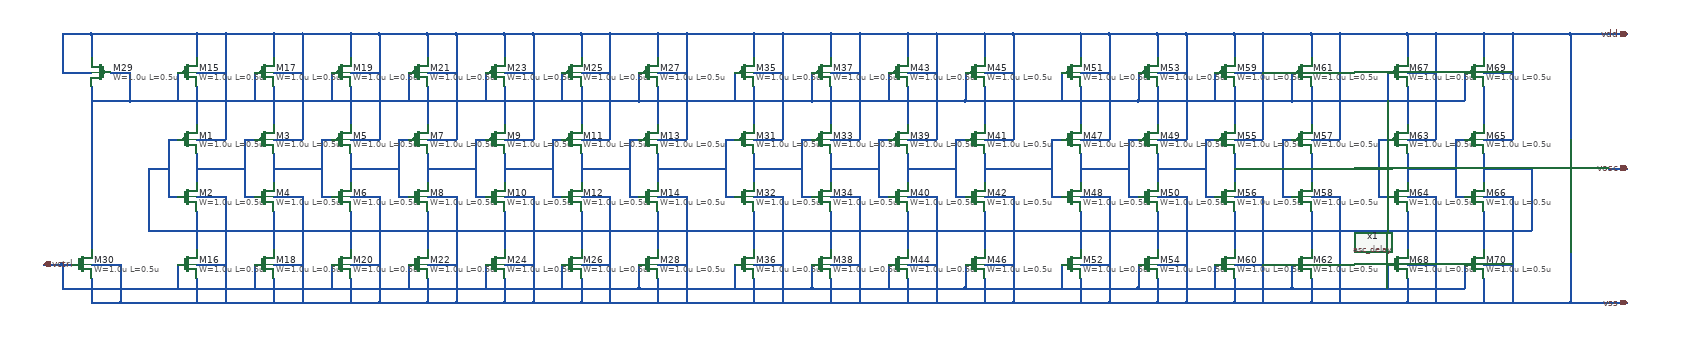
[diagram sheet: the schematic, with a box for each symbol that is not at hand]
v {xschem version=3.4.7 file_version=1.2}
G {}
K {}
V {}
S {}
E {}
N 1840 -1350 1840 -1290 {lab=#net1}
N 2000 -1350 2000 -1290 {lab=#net2}
N 2160 -1350 2160 -1290 {lab=#net3}
N 2320 -1350 2320 -1290 {lab=#net4}
N 2480 -1350 2480 -1290 {lab=#net5}
N 2640 -1350 2640 -1290 {lab=#net6}
N 2800 -1350 2800 -1290 {lab=#net7}
N 1840 -1230 1840 -1170 {lab=#net8}
N 1840 -1110 1840 -1030 {lab=#net9}
N 2000 -1110 2000 -1030 {lab=#net10}
N 2160 -1110 2160 -1030 {lab=#net11}
N 2320 -1110 2320 -1030 {lab=#net12}
N 2480 -1110 2480 -1030 {lab=#net13}
N 2640 -1110 2640 -1030 {lab=#net14}
N 2800 -1110 2800 -1030 {lab=#net15}
N 2000 -1230 2000 -1170 {lab=#net16}
N 2160 -1230 2160 -1170 {lab=#net17}
N 2320 -1230 2320 -1170 {lab=#net18}
N 2480 -1230 2480 -1170 {lab=#net19}
N 2640 -1230 2640 -1170 {lab=#net20}
N 2800 -1230 2800 -1170 {lab=#net21}
N 1780 -1260 1800 -1260 {lab=#net22}
N 1780 -1260 1780 -1140 {lab=#net22}
N 1780 -1140 1800 -1140 {lab=#net22}
N 1940 -1260 1960 -1260 {lab=#net8}
N 1940 -1260 1940 -1140 {lab=#net8}
N 1940 -1140 1960 -1140 {lab=#net8}
N 2100 -1260 2120 -1260 {lab=#net16}
N 2100 -1260 2100 -1140 {lab=#net16}
N 2100 -1140 2120 -1140 {lab=#net16}
N 2260 -1260 2280 -1260 {lab=#net17}
N 2260 -1260 2260 -1140 {lab=#net17}
N 2260 -1140 2280 -1140 {lab=#net17}
N 2420 -1260 2440 -1260 {lab=#net18}
N 2420 -1260 2420 -1140 {lab=#net18}
N 2420 -1140 2440 -1140 {lab=#net18}
N 2580 -1260 2600 -1260 {lab=#net19}
N 2580 -1260 2580 -1140 {lab=#net19}
N 2580 -1140 2600 -1140 {lab=#net19}
N 2740 -1260 2760 -1260 {lab=#net20}
N 2740 -1260 2740 -1140 {lab=#net20}
N 2740 -1140 2760 -1140 {lab=#net20}
N 1840 -1200 1940 -1200 {lab=#net8}
N 2000 -1200 2100 -1200 {lab=#net16}
N 2160 -1200 2260 -1200 {lab=#net17}
N 2320 -1200 2420 -1200 {lab=#net18}
N 2480 -1200 2580 -1200 {lab=#net19}
N 2640 -1200 2740 -1200 {lab=#net20}
N 1740 -1200 1780 -1200 {lab=#net22}
N 1740 -1200 1740 -1070 {lab=#net22}
N 1740 -1070 2900 -1070 {lab=#net22}
N 2800 -1200 2900 -1200 {lab=#net21}
N 1840 -1140 1900 -1140 {lab=#net23}
N 1900 -1140 1900 -920 {lab=#net23}
N 1840 -1000 1900 -1000 {lab=#net23}
N 1840 -970 1840 -920 {lab=#net23}
N 1840 -920 1900 -920 {lab=#net23}
N 2000 -1140 2060 -1140 {lab=#net23}
N 2060 -1140 2060 -920 {lab=#net23}
N 2000 -1000 2060 -1000 {lab=#net23}
N 2000 -970 2000 -920 {lab=#net23}
N 2000 -920 2060 -920 {lab=#net23}
N 2160 -1140 2220 -1140 {lab=#net23}
N 2220 -1140 2220 -920 {lab=#net23}
N 2160 -1000 2220 -1000 {lab=#net23}
N 2160 -970 2160 -920 {lab=#net23}
N 2160 -920 2220 -920 {lab=#net23}
N 2320 -1140 2380 -1140 {lab=#net23}
N 2380 -1140 2380 -920 {lab=#net23}
N 2320 -1000 2380 -1000 {lab=#net23}
N 2320 -970 2320 -920 {lab=#net23}
N 2320 -920 2380 -920 {lab=#net23}
N 2480 -1140 2540 -1140 {lab=#net23}
N 2540 -1140 2540 -920 {lab=#net23}
N 2480 -1000 2540 -1000 {lab=#net23}
N 2480 -970 2480 -920 {lab=#net23}
N 2480 -920 2540 -920 {lab=#net23}
N 2640 -1140 2700 -1140 {lab=#net23}
N 2700 -1140 2700 -920 {lab=#net23}
N 2640 -1000 2700 -1000 {lab=#net23}
N 2640 -970 2640 -920 {lab=#net23}
N 2640 -920 2700 -920 {lab=#net23}
N 2800 -1140 2860 -1140 {lab=#net23}
N 2860 -1140 2860 -920 {lab=#net23}
N 2800 -1000 2860 -1000 {lab=#net23}
N 2800 -970 2800 -920 {lab=#net23}
N 2800 -920 2860 -920 {lab=#net23}
N 1840 -1370 1840 -1350 {lab=#net1}
N 2000 -1370 2000 -1350 {lab=#net2}
N 2160 -1370 2160 -1350 {lab=#net3}
N 2320 -1370 2320 -1350 {lab=#net4}
N 2480 -1370 2480 -1350 {lab=#net5}
N 2640 -1370 2640 -1350 {lab=#net6}
N 2800 -1370 2800 -1350 {lab=#net7}
N 1840 -1260 1900 -1260 {lab=#net24}
N 1900 -1480 1900 -1260 {lab=#net24}
N 1840 -1400 1900 -1400 {lab=#net24}
N 1840 -1480 1840 -1430 {lab=#net24}
N 1840 -1480 1900 -1480 {lab=#net24}
N 2000 -1260 2060 -1260 {lab=#net24}
N 2060 -1480 2060 -1260 {lab=#net24}
N 2000 -1400 2060 -1400 {lab=#net24}
N 2000 -1480 2000 -1430 {lab=#net24}
N 2000 -1480 2060 -1480 {lab=#net24}
N 2160 -1260 2220 -1260 {lab=#net24}
N 2220 -1480 2220 -1260 {lab=#net24}
N 2160 -1400 2220 -1400 {lab=#net24}
N 2160 -1480 2160 -1430 {lab=#net24}
N 2160 -1480 2220 -1480 {lab=#net24}
N 2320 -1260 2380 -1260 {lab=#net24}
N 2380 -1480 2380 -1260 {lab=#net24}
N 2320 -1400 2380 -1400 {lab=#net24}
N 2320 -1480 2320 -1430 {lab=#net24}
N 2320 -1480 2380 -1480 {lab=#net24}
N 2480 -1260 2540 -1260 {lab=#net24}
N 2540 -1480 2540 -1260 {lab=#net24}
N 2480 -1400 2540 -1400 {lab=#net24}
N 2480 -1480 2480 -1430 {lab=#net24}
N 2480 -1480 2540 -1480 {lab=#net24}
N 2640 -1260 2700 -1260 {lab=#net24}
N 2700 -1480 2700 -1260 {lab=#net24}
N 2640 -1400 2700 -1400 {lab=#net24}
N 2640 -1480 2640 -1430 {lab=#net24}
N 2640 -1480 2700 -1480 {lab=#net24}
N 2800 -1260 2860 -1260 {lab=#net24}
N 2860 -1480 2860 -1260 {lab=#net24}
N 2800 -1400 2860 -1400 {lab=#net24}
N 2800 -1480 2800 -1430 {lab=#net24}
N 2800 -1480 2860 -1480 {lab=#net24}
N 1900 -1480 2000 -1480 {lab=#net24}
N 2060 -1480 2160 -1480 {lab=#net24}
N 2220 -1480 2320 -1480 {lab=#net24}
N 2380 -1480 2480 -1480 {lab=#net24}
N 2540 -1480 2640 -1480 {lab=#net24}
N 2700 -1480 2800 -1480 {lab=#net24}
N 1900 -920 2000 -920 {lab=#net23}
N 2060 -920 2160 -920 {lab=#net23}
N 2220 -920 2320 -920 {lab=#net23}
N 2380 -920 2480 -920 {lab=#net23}
N 2540 -920 2640 -920 {lab=#net23}
N 2700 -920 2800 -920 {lab=#net23}
N 1560 -1400 1620 -1400 {lab=#net24}
N 1620 -1480 1620 -1430 {lab=#net24}
N 1620 -1480 1680 -1480 {lab=#net24}
N 1560 -1480 1560 -1400 {lab=#net24}
N 1560 -1480 1620 -1480 {lab=#net24}
N 1620 -1000 1680 -1000 {lab=#net23}
N 1620 -970 1620 -920 {lab=#net23}
N 1620 -920 1680 -920 {lab=#net23}
N 1680 -1000 1680 -920 {lab=#net23}
N 1620 -1370 1620 -1030 {lab=#net25}
N 1620 -1340 1700 -1340 {lab=#net25}
N 1660 -1400 1700 -1400 {lab=#net25}
N 1700 -1400 1700 -1340 {lab=#net25}
N 1680 -920 1840 -920 {lab=#net23}
N 1680 -1480 1840 -1480 {lab=#net24}
N 2860 -1480 2900 -1480 {lab=#net24}
N 2860 -920 2900 -920 {lab=#net23}
N 2900 -1200 2920 -1200 {lab=#net21}
N 2920 -1200 2940 -1200 {lab=#net21}
N 1700 -1340 2760 -1340 {lab=#net25}
N 2760 -1400 2760 -1340 {lab=#net25}
N 2600 -1400 2600 -1340 {lab=#net25}
N 2440 -1400 2440 -1340 {lab=#net25}
N 2280 -1400 2280 -1340 {lab=#net25}
N 2120 -1400 2120 -1340 {lab=#net25}
N 1960 -1400 1960 -1340 {lab=#net25}
N 1800 -1400 1800 -1340 {lab=#net25}
N 1560 -1000 1560 -950 {lab=vctrl}
N 1560 -950 2760 -950 {lab=vctrl}
N 2760 -1000 2760 -950 {lab=vctrl}
N 2600 -1000 2600 -960 {lab=vctrl}
N 2600 -960 2600 -950 {lab=vctrl}
N 2440 -1000 2440 -950 {lab=vctrl}
N 2280 -1000 2280 -950 {lab=vctrl}
N 2120 -1000 2120 -950 {lab=vctrl}
N 1960 -1000 1960 -950 {lab=vctrl}
N 1800 -1000 1800 -950 {lab=vctrl}
N 1560 -1000 1580 -1000 {lab=vctrl}
N 4780 -1200 4820 -1200 {lab=vosc}
N 4700 -1140 4700 -920 {lab=vss}
N 4700 -1480 4700 -1260 {lab=vdd}
N 4700 -1480 4820 -1480 {lab=vdd}
N 4700 -920 4820 -920 {lab=vss}
N 1520 -1000 1560 -1000 {lab=vctrl}
N 3000 -1350 3000 -1290 {lab=#net26}
N 3160 -1350 3160 -1290 {lab=#net27}
N 3000 -1110 3000 -1030 {lab=#net28}
N 3160 -1110 3160 -1030 {lab=#net29}
N 3000 -1230 3000 -1170 {lab=#net30}
N 3160 -1230 3160 -1170 {lab=#net31}
N 2940 -1260 2960 -1260 {lab=#net21}
N 2940 -1260 2940 -1140 {lab=#net21}
N 2940 -1140 2960 -1140 {lab=#net21}
N 3100 -1260 3120 -1260 {lab=#net30}
N 3100 -1260 3100 -1140 {lab=#net30}
N 3100 -1140 3120 -1140 {lab=#net30}
N 3000 -1200 3100 -1200 {lab=#net30}
N 3160 -1200 3260 -1200 {lab=#net31}
N 3000 -1140 3060 -1140 {lab=#net23}
N 3060 -1140 3060 -920 {lab=#net23}
N 3000 -1000 3060 -1000 {lab=#net23}
N 3000 -970 3000 -920 {lab=#net23}
N 3000 -920 3060 -920 {lab=#net23}
N 3160 -1140 3220 -1140 {lab=#net23}
N 3220 -1140 3220 -920 {lab=#net23}
N 3160 -1000 3220 -1000 {lab=#net23}
N 3160 -970 3160 -920 {lab=#net23}
N 3160 -920 3220 -920 {lab=#net23}
N 3000 -1370 3000 -1350 {lab=#net26}
N 3160 -1370 3160 -1350 {lab=#net27}
N 3000 -1260 3060 -1260 {lab=#net24}
N 3060 -1480 3060 -1260 {lab=#net24}
N 3000 -1400 3060 -1400 {lab=#net24}
N 3000 -1480 3000 -1430 {lab=#net24}
N 3000 -1480 3060 -1480 {lab=#net24}
N 3160 -1260 3220 -1260 {lab=#net24}
N 3220 -1480 3220 -1260 {lab=#net24}
N 3160 -1400 3220 -1400 {lab=#net24}
N 3160 -1480 3160 -1430 {lab=#net24}
N 3160 -1480 3220 -1480 {lab=#net24}
N 3060 -1480 3160 -1480 {lab=#net24}
N 3060 -920 3160 -920 {lab=#net23}
N 3220 -1480 3260 -1480 {lab=#net24}
N 3220 -920 3260 -920 {lab=#net23}
N 3120 -1400 3120 -1340 {lab=#net25}
N 2960 -1400 2960 -1340 {lab=#net25}
N 3120 -1000 3120 -950 {lab=vctrl}
N 2960 -1000 2960 -960 {lab=vctrl}
N 2960 -960 2960 -950 {lab=vctrl}
N 2900 -1070 3260 -1070 {lab=#net22}
N 2900 -1480 3000 -1480 {lab=#net24}
N 2900 -920 3000 -920 {lab=#net23}
N 2760 -950 3120 -950 {lab=vctrl}
N 2760 -1340 3120 -1340 {lab=#net25}
N 3320 -1350 3320 -1290 {lab=#net32}
N 3480 -1350 3480 -1290 {lab=#net33}
N 3320 -1110 3320 -1030 {lab=#net34}
N 3480 -1110 3480 -1030 {lab=#net35}
N 3320 -1230 3320 -1170 {lab=#net36}
N 3480 -1230 3480 -1170 {lab=#net37}
N 3260 -1260 3280 -1260 {lab=#net31}
N 3260 -1260 3260 -1140 {lab=#net31}
N 3260 -1140 3280 -1140 {lab=#net31}
N 3420 -1260 3440 -1260 {lab=#net36}
N 3420 -1260 3420 -1140 {lab=#net36}
N 3420 -1140 3440 -1140 {lab=#net36}
N 3320 -1200 3420 -1200 {lab=#net36}
N 3480 -1200 3580 -1200 {lab=#net37}
N 3320 -1140 3380 -1140 {lab=#net23}
N 3380 -1140 3380 -920 {lab=#net23}
N 3320 -1000 3380 -1000 {lab=#net23}
N 3320 -970 3320 -920 {lab=#net23}
N 3320 -920 3380 -920 {lab=#net23}
N 3480 -1140 3540 -1140 {lab=#net23}
N 3540 -1140 3540 -920 {lab=#net23}
N 3480 -1000 3540 -1000 {lab=#net23}
N 3480 -970 3480 -920 {lab=#net23}
N 3480 -920 3540 -920 {lab=#net23}
N 3320 -1370 3320 -1350 {lab=#net32}
N 3480 -1370 3480 -1350 {lab=#net33}
N 3320 -1260 3380 -1260 {lab=#net24}
N 3380 -1480 3380 -1260 {lab=#net24}
N 3320 -1400 3380 -1400 {lab=#net24}
N 3320 -1480 3320 -1430 {lab=#net24}
N 3320 -1480 3380 -1480 {lab=#net24}
N 3480 -1260 3540 -1260 {lab=#net24}
N 3540 -1480 3540 -1260 {lab=#net24}
N 3480 -1400 3540 -1400 {lab=#net24}
N 3480 -1480 3480 -1430 {lab=#net24}
N 3480 -1480 3540 -1480 {lab=#net24}
N 3380 -1480 3480 -1480 {lab=#net24}
N 3380 -920 3480 -920 {lab=#net23}
N 3540 -1480 3580 -1480 {lab=#net24}
N 3540 -920 3580 -920 {lab=#net23}
N 3580 -1200 3600 -1200 {lab=#net37}
N 3600 -1200 3620 -1200 {lab=#net37}
N 3440 -1400 3440 -1340 {lab=#net25}
N 3280 -1400 3280 -1340 {lab=#net25}
N 3440 -1000 3440 -950 {lab=vctrl}
N 3280 -1000 3280 -960 {lab=vctrl}
N 3280 -960 3280 -950 {lab=vctrl}
N 3680 -1350 3680 -1290 {lab=#net38}
N 3840 -1350 3840 -1290 {lab=#net39}
N 3680 -1110 3680 -1030 {lab=#net40}
N 3840 -1110 3840 -1030 {lab=#net41}
N 3680 -1230 3680 -1170 {lab=#net42}
N 3840 -1230 3840 -1170 {lab=#net43}
N 3620 -1260 3640 -1260 {lab=#net37}
N 3620 -1260 3620 -1140 {lab=#net37}
N 3620 -1140 3640 -1140 {lab=#net37}
N 3780 -1260 3800 -1260 {lab=#net42}
N 3780 -1260 3780 -1140 {lab=#net42}
N 3780 -1140 3800 -1140 {lab=#net42}
N 3680 -1200 3780 -1200 {lab=#net42}
N 3840 -1200 3940 -1200 {lab=#net43}
N 3680 -1140 3740 -1140 {lab=#net23}
N 3740 -1140 3740 -920 {lab=#net23}
N 3680 -1000 3740 -1000 {lab=#net23}
N 3680 -970 3680 -920 {lab=#net23}
N 3680 -920 3740 -920 {lab=#net23}
N 3840 -1140 3900 -1140 {lab=#net23}
N 3900 -1140 3900 -920 {lab=#net23}
N 3840 -1000 3900 -1000 {lab=#net23}
N 3840 -970 3840 -920 {lab=#net23}
N 3840 -920 3900 -920 {lab=#net23}
N 3680 -1370 3680 -1350 {lab=#net38}
N 3840 -1370 3840 -1350 {lab=#net39}
N 3680 -1260 3740 -1260 {lab=#net24}
N 3740 -1480 3740 -1260 {lab=#net24}
N 3680 -1400 3740 -1400 {lab=#net24}
N 3680 -1480 3680 -1430 {lab=#net24}
N 3680 -1480 3740 -1480 {lab=#net24}
N 3840 -1260 3900 -1260 {lab=#net24}
N 3900 -1480 3900 -1260 {lab=#net24}
N 3840 -1400 3900 -1400 {lab=#net24}
N 3840 -1480 3840 -1430 {lab=#net24}
N 3840 -1480 3900 -1480 {lab=#net24}
N 3740 -1480 3840 -1480 {lab=#net24}
N 3740 -920 3840 -920 {lab=#net23}
N 3800 -1400 3800 -1340 {lab=#net25}
N 3640 -1400 3640 -1340 {lab=#net25}
N 3800 -1000 3800 -950 {lab=vctrl}
N 3640 -1000 3640 -960 {lab=vctrl}
N 3640 -960 3640 -950 {lab=vctrl}
N 3580 -1070 3940 -1070 {lab=#net22}
N 3580 -1480 3680 -1480 {lab=#net24}
N 3580 -920 3680 -920 {lab=#net23}
N 3440 -950 3800 -950 {lab=vctrl}
N 3440 -1340 3800 -1340 {lab=#net25}
N 3120 -950 3440 -950 {lab=vctrl}
N 3260 -920 3320 -920 {lab=#net23}
N 3260 -1070 3580 -1070 {lab=#net22}
N 3130 -1340 3440 -1340 {lab=#net25}
N 3120 -1340 3130 -1340 {lab=#net25}
N 3260 -1480 3320 -1480 {lab=#net24}
N 4620 -920 4700 -920 {lab=vss}
N 4620 -1480 4700 -1480 {lab=vdd}
N 3900 -1480 3940 -1480 {lab=#net24}
N 3900 -920 3940 -920 {lab=#net23}
N 4000 -1350 4000 -1290 {lab=#net44}
N 4160 -1350 4160 -1290 {lab=#net45}
N 4000 -1110 4000 -1030 {lab=#net46}
N 4160 -1110 4160 -1030 {lab=#net47}
N 4000 -1230 4000 -1170 {lab=#net48}
N 4160 -1230 4160 -1170 {lab=#net49}
N 3940 -1260 3960 -1260 {lab=#net43}
N 3940 -1260 3940 -1140 {lab=#net43}
N 3940 -1140 3960 -1140 {lab=#net43}
N 4100 -1260 4120 -1260 {lab=#net48}
N 4100 -1260 4100 -1140 {lab=#net48}
N 4100 -1140 4120 -1140 {lab=#net48}
N 4000 -1200 4100 -1200 {lab=#net48}
N 4160 -1200 4260 -1200 {lab=#net49}
N 4000 -1140 4060 -1140 {lab=#net23}
N 4060 -1140 4060 -920 {lab=#net23}
N 4000 -1000 4060 -1000 {lab=#net23}
N 4000 -970 4000 -920 {lab=#net23}
N 4000 -920 4060 -920 {lab=#net23}
N 4160 -1140 4220 -1140 {lab=#net23}
N 4220 -1140 4220 -920 {lab=#net23}
N 4160 -1000 4220 -1000 {lab=#net23}
N 4160 -970 4160 -920 {lab=#net23}
N 4160 -920 4220 -920 {lab=#net23}
N 4000 -1370 4000 -1350 {lab=#net44}
N 4160 -1370 4160 -1350 {lab=#net45}
N 4000 -1260 4060 -1260 {lab=#net24}
N 4060 -1480 4060 -1260 {lab=#net24}
N 4000 -1400 4060 -1400 {lab=#net24}
N 4000 -1480 4000 -1430 {lab=#net24}
N 4000 -1480 4060 -1480 {lab=#net24}
N 4160 -1260 4220 -1260 {lab=#net24}
N 4220 -1480 4220 -1260 {lab=#net24}
N 4160 -1400 4220 -1400 {lab=#net24}
N 4160 -1480 4160 -1430 {lab=#net24}
N 4160 -1480 4220 -1480 {lab=#net24}
N 4060 -1480 4160 -1480 {lab=#net24}
N 4060 -920 4160 -920 {lab=#net23}
N 4220 -1480 4260 -1480 {lab=#net24}
N 4220 -920 4260 -920 {lab=#net23}
N 4260 -1200 4280 -1200 {lab=#net49}
N 4280 -1200 4300 -1200 {lab=#net49}
N 4120 -1400 4120 -1340 {lab=#net25}
N 3960 -1400 3960 -1340 {lab=#net25}
N 4120 -1000 4120 -950 {lab=vctrl}
N 3960 -1000 3960 -960 {lab=vctrl}
N 3960 -960 3960 -950 {lab=vctrl}
N 4360 -1350 4360 -1290 {lab=#net50}
N 4520 -1350 4520 -1290 {lab=#net51}
N 4360 -1110 4360 -1030 {lab=#net52}
N 4520 -1110 4520 -1030 {lab=#net53}
N 4360 -1230 4360 -1170 {lab=#net54}
N 4520 -1230 4520 -1170 {lab=#net22}
N 4300 -1260 4320 -1260 {lab=#net49}
N 4300 -1260 4300 -1140 {lab=#net49}
N 4300 -1140 4320 -1140 {lab=#net49}
N 4460 -1260 4480 -1260 {lab=#net54}
N 4460 -1260 4460 -1140 {lab=#net54}
N 4460 -1140 4480 -1140 {lab=#net54}
N 4360 -1200 4460 -1200 {lab=#net54}
N 4520 -1200 4620 -1200 {lab=#net22}
N 4360 -1140 4420 -1140 {lab=#net23}
N 4420 -1140 4420 -920 {lab=#net23}
N 4360 -1000 4420 -1000 {lab=#net23}
N 4360 -970 4360 -920 {lab=#net23}
N 4360 -920 4420 -920 {lab=#net23}
N 4520 -1140 4580 -1140 {lab=#net23}
N 4580 -1140 4580 -920 {lab=#net23}
N 4520 -1000 4580 -1000 {lab=#net23}
N 4520 -970 4520 -920 {lab=#net23}
N 4520 -920 4580 -920 {lab=#net23}
N 4360 -1370 4360 -1350 {lab=#net50}
N 4520 -1370 4520 -1350 {lab=#net51}
N 4360 -1260 4420 -1260 {lab=#net24}
N 4420 -1480 4420 -1260 {lab=#net24}
N 4360 -1400 4420 -1400 {lab=#net24}
N 4360 -1480 4360 -1430 {lab=#net24}
N 4360 -1480 4420 -1480 {lab=#net24}
N 4520 -1260 4580 -1260 {lab=#net24}
N 4580 -1480 4580 -1260 {lab=#net24}
N 4520 -1400 4580 -1400 {lab=#net24}
N 4520 -1480 4520 -1430 {lab=#net24}
N 4520 -1480 4580 -1480 {lab=#net24}
N 4420 -1480 4520 -1480 {lab=#net24}
N 4420 -920 4520 -920 {lab=#net23}
N 4580 -1480 4620 -1480 {lab=#net24}
N 4580 -920 4620 -920 {lab=#net23}
N 4480 -1400 4480 -1340 {lab=#net25}
N 4320 -1400 4320 -1340 {lab=#net25}
N 4480 -1000 4480 -950 {lab=vctrl}
N 4320 -1000 4320 -960 {lab=vctrl}
N 4320 -960 4320 -950 {lab=vctrl}
N 4260 -1070 4620 -1070 {lab=#net22}
N 4260 -1480 4360 -1480 {lab=#net24}
N 4260 -920 4360 -920 {lab=#net23}
N 4120 -950 4480 -950 {lab=vctrl}
N 4120 -1340 4480 -1340 {lab=#net25}
N 3940 -920 4000 -920 {lab=#net23}
N 3940 -1070 4260 -1070 {lab=#net22}
N 3940 -1480 4000 -1480 {lab=#net24}
N 4620 -1200 4620 -1070 {lab=#net22}
N 3800 -950 4120 -950 {lab=vctrl}
N 3800 -1340 4120 -1340 {lab=#net25}
C {symbols/pfet_03v3.sym} 1820 -1260 0 0 {name=M1
L=0.5u
W=1.0u
nf=1
m=1
ad="'int((nf+1)/2) * W/nf * 0.18u'"
pd="'2*int((nf+1)/2) * (W/nf + 0.18u)'"
as="'int((nf+2)/2) * W/nf * 0.18u'"
ps="'2*int((nf+2)/2) * (W/nf + 0.18u)'"
nrd="'0.18u / W'" nrs="'0.18u / W'"
sa=0 sb=0 sd=0
model=pfet_03v3
spiceprefix=X
}
C {symbols/nfet_03v3.sym} 1820 -1140 0 0 {name=M2
L=0.5u
W=1.0u
nf=1
m=1
ad="'int((nf+1)/2) * W/nf * 0.18u'"
pd="'2*int((nf+1)/2) * (W/nf + 0.18u)'"
as="'int((nf+2)/2) * W/nf * 0.18u'"
ps="'2*int((nf+2)/2) * (W/nf + 0.18u)'"
nrd="'0.18u / W'" nrs="'0.18u / W'"
sa=0 sb=0 sd=0
model=nfet_03v3
spiceprefix=X
}
C {symbols/pfet_03v3.sym} 1980 -1260 0 0 {name=M3
L=0.5u
W=1.0u
nf=1
m=1
ad="'int((nf+1)/2) * W/nf * 0.18u'"
pd="'2*int((nf+1)/2) * (W/nf + 0.18u)'"
as="'int((nf+2)/2) * W/nf * 0.18u'"
ps="'2*int((nf+2)/2) * (W/nf + 0.18u)'"
nrd="'0.18u / W'" nrs="'0.18u / W'"
sa=0 sb=0 sd=0
model=pfet_03v3
spiceprefix=X
}
C {symbols/nfet_03v3.sym} 1980 -1140 0 0 {name=M4
L=0.5u
W=1.0u
nf=1
m=1
ad="'int((nf+1)/2) * W/nf * 0.18u'"
pd="'2*int((nf+1)/2) * (W/nf + 0.18u)'"
as="'int((nf+2)/2) * W/nf * 0.18u'"
ps="'2*int((nf+2)/2) * (W/nf + 0.18u)'"
nrd="'0.18u / W'" nrs="'0.18u / W'"
sa=0 sb=0 sd=0
model=nfet_03v3
spiceprefix=X
}
C {symbols/pfet_03v3.sym} 2140 -1260 0 0 {name=M5
L=0.5u
W=1.0u
nf=1
m=1
ad="'int((nf+1)/2) * W/nf * 0.18u'"
pd="'2*int((nf+1)/2) * (W/nf + 0.18u)'"
as="'int((nf+2)/2) * W/nf * 0.18u'"
ps="'2*int((nf+2)/2) * (W/nf + 0.18u)'"
nrd="'0.18u / W'" nrs="'0.18u / W'"
sa=0 sb=0 sd=0
model=pfet_03v3
spiceprefix=X
}
C {symbols/nfet_03v3.sym} 2140 -1140 0 0 {name=M6
L=0.5u
W=1.0u
nf=1
m=1
ad="'int((nf+1)/2) * W/nf * 0.18u'"
pd="'2*int((nf+1)/2) * (W/nf + 0.18u)'"
as="'int((nf+2)/2) * W/nf * 0.18u'"
ps="'2*int((nf+2)/2) * (W/nf + 0.18u)'"
nrd="'0.18u / W'" nrs="'0.18u / W'"
sa=0 sb=0 sd=0
model=nfet_03v3
spiceprefix=X
}
C {symbols/pfet_03v3.sym} 2300 -1260 0 0 {name=M7
L=0.5u
W=1.0u
nf=1
m=1
ad="'int((nf+1)/2) * W/nf * 0.18u'"
pd="'2*int((nf+1)/2) * (W/nf + 0.18u)'"
as="'int((nf+2)/2) * W/nf * 0.18u'"
ps="'2*int((nf+2)/2) * (W/nf + 0.18u)'"
nrd="'0.18u / W'" nrs="'0.18u / W'"
sa=0 sb=0 sd=0
model=pfet_03v3
spiceprefix=X
}
C {symbols/nfet_03v3.sym} 2300 -1140 0 0 {name=M8
L=0.5u
W=1.0u
nf=1
m=1
ad="'int((nf+1)/2) * W/nf * 0.18u'"
pd="'2*int((nf+1)/2) * (W/nf + 0.18u)'"
as="'int((nf+2)/2) * W/nf * 0.18u'"
ps="'2*int((nf+2)/2) * (W/nf + 0.18u)'"
nrd="'0.18u / W'" nrs="'0.18u / W'"
sa=0 sb=0 sd=0
model=nfet_03v3
spiceprefix=X
}
C {symbols/pfet_03v3.sym} 2460 -1260 0 0 {name=M9
L=0.5u
W=1.0u
nf=1
m=1
ad="'int((nf+1)/2) * W/nf * 0.18u'"
pd="'2*int((nf+1)/2) * (W/nf + 0.18u)'"
as="'int((nf+2)/2) * W/nf * 0.18u'"
ps="'2*int((nf+2)/2) * (W/nf + 0.18u)'"
nrd="'0.18u / W'" nrs="'0.18u / W'"
sa=0 sb=0 sd=0
model=pfet_03v3
spiceprefix=X
}
C {symbols/nfet_03v3.sym} 2460 -1140 0 0 {name=M10
L=0.5u
W=1.0u
nf=1
m=1
ad="'int((nf+1)/2) * W/nf * 0.18u'"
pd="'2*int((nf+1)/2) * (W/nf + 0.18u)'"
as="'int((nf+2)/2) * W/nf * 0.18u'"
ps="'2*int((nf+2)/2) * (W/nf + 0.18u)'"
nrd="'0.18u / W'" nrs="'0.18u / W'"
sa=0 sb=0 sd=0
model=nfet_03v3
spiceprefix=X
}
C {symbols/pfet_03v3.sym} 2620 -1260 0 0 {name=M11
L=0.5u
W=1.0u
nf=1
m=1
ad="'int((nf+1)/2) * W/nf * 0.18u'"
pd="'2*int((nf+1)/2) * (W/nf + 0.18u)'"
as="'int((nf+2)/2) * W/nf * 0.18u'"
ps="'2*int((nf+2)/2) * (W/nf + 0.18u)'"
nrd="'0.18u / W'" nrs="'0.18u / W'"
sa=0 sb=0 sd=0
model=pfet_03v3
spiceprefix=X
}
C {symbols/nfet_03v3.sym} 2620 -1140 0 0 {name=M12
L=0.5u
W=1.0u
nf=1
m=1
ad="'int((nf+1)/2) * W/nf * 0.18u'"
pd="'2*int((nf+1)/2) * (W/nf + 0.18u)'"
as="'int((nf+2)/2) * W/nf * 0.18u'"
ps="'2*int((nf+2)/2) * (W/nf + 0.18u)'"
nrd="'0.18u / W'" nrs="'0.18u / W'"
sa=0 sb=0 sd=0
model=nfet_03v3
spiceprefix=X
}
C {symbols/pfet_03v3.sym} 2780 -1260 0 0 {name=M13
L=0.5u
W=1.0u
nf=1
m=1
ad="'int((nf+1)/2) * W/nf * 0.18u'"
pd="'2*int((nf+1)/2) * (W/nf + 0.18u)'"
as="'int((nf+2)/2) * W/nf * 0.18u'"
ps="'2*int((nf+2)/2) * (W/nf + 0.18u)'"
nrd="'0.18u / W'" nrs="'0.18u / W'"
sa=0 sb=0 sd=0
model=pfet_03v3
spiceprefix=X
}
C {symbols/nfet_03v3.sym} 2780 -1140 0 0 {name=M14
L=0.5u
W=1.0u
nf=1
m=1
ad="'int((nf+1)/2) * W/nf * 0.18u'"
pd="'2*int((nf+1)/2) * (W/nf + 0.18u)'"
as="'int((nf+2)/2) * W/nf * 0.18u'"
ps="'2*int((nf+2)/2) * (W/nf + 0.18u)'"
nrd="'0.18u / W'" nrs="'0.18u / W'"
sa=0 sb=0 sd=0
model=nfet_03v3
spiceprefix=X
}
C {symbols/pfet_03v3.sym} 1820 -1400 0 0 {name=M15
L=0.5u
W=1.0u
nf=1
m=1
ad="'int((nf+1)/2) * W/nf * 0.18u'"
pd="'2*int((nf+1)/2) * (W/nf + 0.18u)'"
as="'int((nf+2)/2) * W/nf * 0.18u'"
ps="'2*int((nf+2)/2) * (W/nf + 0.18u)'"
nrd="'0.18u / W'" nrs="'0.18u / W'"
sa=0 sb=0 sd=0
model=pfet_03v3
spiceprefix=X
}
C {symbols/nfet_03v3.sym} 1820 -1000 0 0 {name=M16
L=0.5u
W=1.0u
nf=1
m=1
ad="'int((nf+1)/2) * W/nf * 0.18u'"
pd="'2*int((nf+1)/2) * (W/nf + 0.18u)'"
as="'int((nf+2)/2) * W/nf * 0.18u'"
ps="'2*int((nf+2)/2) * (W/nf + 0.18u)'"
nrd="'0.18u / W'" nrs="'0.18u / W'"
sa=0 sb=0 sd=0
model=nfet_03v3
spiceprefix=X
}
C {symbols/pfet_03v3.sym} 1980 -1400 0 0 {name=M17
L=0.5u
W=1.0u
nf=1
m=1
ad="'int((nf+1)/2) * W/nf * 0.18u'"
pd="'2*int((nf+1)/2) * (W/nf + 0.18u)'"
as="'int((nf+2)/2) * W/nf * 0.18u'"
ps="'2*int((nf+2)/2) * (W/nf + 0.18u)'"
nrd="'0.18u / W'" nrs="'0.18u / W'"
sa=0 sb=0 sd=0
model=pfet_03v3
spiceprefix=X
}
C {symbols/nfet_03v3.sym} 1980 -1000 0 0 {name=M18
L=0.5u
W=1.0u
nf=1
m=1
ad="'int((nf+1)/2) * W/nf * 0.18u'"
pd="'2*int((nf+1)/2) * (W/nf + 0.18u)'"
as="'int((nf+2)/2) * W/nf * 0.18u'"
ps="'2*int((nf+2)/2) * (W/nf + 0.18u)'"
nrd="'0.18u / W'" nrs="'0.18u / W'"
sa=0 sb=0 sd=0
model=nfet_03v3
spiceprefix=X
}
C {symbols/pfet_03v3.sym} 2140 -1400 0 0 {name=M19
L=0.5u
W=1.0u
nf=1
m=1
ad="'int((nf+1)/2) * W/nf * 0.18u'"
pd="'2*int((nf+1)/2) * (W/nf + 0.18u)'"
as="'int((nf+2)/2) * W/nf * 0.18u'"
ps="'2*int((nf+2)/2) * (W/nf + 0.18u)'"
nrd="'0.18u / W'" nrs="'0.18u / W'"
sa=0 sb=0 sd=0
model=pfet_03v3
spiceprefix=X
}
C {symbols/nfet_03v3.sym} 2140 -1000 0 0 {name=M20
L=0.5u
W=1.0u
nf=1
m=1
ad="'int((nf+1)/2) * W/nf * 0.18u'"
pd="'2*int((nf+1)/2) * (W/nf + 0.18u)'"
as="'int((nf+2)/2) * W/nf * 0.18u'"
ps="'2*int((nf+2)/2) * (W/nf + 0.18u)'"
nrd="'0.18u / W'" nrs="'0.18u / W'"
sa=0 sb=0 sd=0
model=nfet_03v3
spiceprefix=X
}
C {symbols/pfet_03v3.sym} 2300 -1400 0 0 {name=M21
L=0.5u
W=1.0u
nf=1
m=1
ad="'int((nf+1)/2) * W/nf * 0.18u'"
pd="'2*int((nf+1)/2) * (W/nf + 0.18u)'"
as="'int((nf+2)/2) * W/nf * 0.18u'"
ps="'2*int((nf+2)/2) * (W/nf + 0.18u)'"
nrd="'0.18u / W'" nrs="'0.18u / W'"
sa=0 sb=0 sd=0
model=pfet_03v3
spiceprefix=X
}
C {symbols/nfet_03v3.sym} 2300 -1000 0 0 {name=M22
L=0.5u
W=1.0u
nf=1
m=1
ad="'int((nf+1)/2) * W/nf * 0.18u'"
pd="'2*int((nf+1)/2) * (W/nf + 0.18u)'"
as="'int((nf+2)/2) * W/nf * 0.18u'"
ps="'2*int((nf+2)/2) * (W/nf + 0.18u)'"
nrd="'0.18u / W'" nrs="'0.18u / W'"
sa=0 sb=0 sd=0
model=nfet_03v3
spiceprefix=X
}
C {symbols/pfet_03v3.sym} 2460 -1400 0 0 {name=M23
L=0.5u
W=1.0u
nf=1
m=1
ad="'int((nf+1)/2) * W/nf * 0.18u'"
pd="'2*int((nf+1)/2) * (W/nf + 0.18u)'"
as="'int((nf+2)/2) * W/nf * 0.18u'"
ps="'2*int((nf+2)/2) * (W/nf + 0.18u)'"
nrd="'0.18u / W'" nrs="'0.18u / W'"
sa=0 sb=0 sd=0
model=pfet_03v3
spiceprefix=X
}
C {symbols/nfet_03v3.sym} 2460 -1000 0 0 {name=M24
L=0.5u
W=1.0u
nf=1
m=1
ad="'int((nf+1)/2) * W/nf * 0.18u'"
pd="'2*int((nf+1)/2) * (W/nf + 0.18u)'"
as="'int((nf+2)/2) * W/nf * 0.18u'"
ps="'2*int((nf+2)/2) * (W/nf + 0.18u)'"
nrd="'0.18u / W'" nrs="'0.18u / W'"
sa=0 sb=0 sd=0
model=nfet_03v3
spiceprefix=X
}
C {symbols/pfet_03v3.sym} 2620 -1400 0 0 {name=M25
L=0.5u
W=1.0u
nf=1
m=1
ad="'int((nf+1)/2) * W/nf * 0.18u'"
pd="'2*int((nf+1)/2) * (W/nf + 0.18u)'"
as="'int((nf+2)/2) * W/nf * 0.18u'"
ps="'2*int((nf+2)/2) * (W/nf + 0.18u)'"
nrd="'0.18u / W'" nrs="'0.18u / W'"
sa=0 sb=0 sd=0
model=pfet_03v3
spiceprefix=X
}
C {symbols/nfet_03v3.sym} 2620 -1000 0 0 {name=M26
L=0.5u
W=1.0u
nf=1
m=1
ad="'int((nf+1)/2) * W/nf * 0.18u'"
pd="'2*int((nf+1)/2) * (W/nf + 0.18u)'"
as="'int((nf+2)/2) * W/nf * 0.18u'"
ps="'2*int((nf+2)/2) * (W/nf + 0.18u)'"
nrd="'0.18u / W'" nrs="'0.18u / W'"
sa=0 sb=0 sd=0
model=nfet_03v3
spiceprefix=X
}
C {symbols/pfet_03v3.sym} 2780 -1400 0 0 {name=M27
L=0.5u
W=1.0u
nf=1
m=1
ad="'int((nf+1)/2) * W/nf * 0.18u'"
pd="'2*int((nf+1)/2) * (W/nf + 0.18u)'"
as="'int((nf+2)/2) * W/nf * 0.18u'"
ps="'2*int((nf+2)/2) * (W/nf + 0.18u)'"
nrd="'0.18u / W'" nrs="'0.18u / W'"
sa=0 sb=0 sd=0
model=pfet_03v3
spiceprefix=X
}
C {symbols/nfet_03v3.sym} 2780 -1000 0 0 {name=M28
L=0.5u
W=1.0u
nf=1
m=1
ad="'int((nf+1)/2) * W/nf * 0.18u'"
pd="'2*int((nf+1)/2) * (W/nf + 0.18u)'"
as="'int((nf+2)/2) * W/nf * 0.18u'"
ps="'2*int((nf+2)/2) * (W/nf + 0.18u)'"
nrd="'0.18u / W'" nrs="'0.18u / W'"
sa=0 sb=0 sd=0
model=nfet_03v3
spiceprefix=X
}
C {symbols/pfet_03v3.sym} 1640 -1400 0 1 {name=M29
L=0.5u
W=1.0u
nf=1
m=1
ad="'int((nf+1)/2) * W/nf * 0.18u'"
pd="'2*int((nf+1)/2) * (W/nf + 0.18u)'"
as="'int((nf+2)/2) * W/nf * 0.18u'"
ps="'2*int((nf+2)/2) * (W/nf + 0.18u)'"
nrd="'0.18u / W'" nrs="'0.18u / W'"
sa=0 sb=0 sd=0
model=pfet_03v3
spiceprefix=X
}
C {symbols/nfet_03v3.sym} 1600 -1000 0 0 {name=M30
L=0.5u
W=1.0u
nf=1
m=1
ad="'int((nf+1)/2) * W/nf * 0.18u'"
pd="'2*int((nf+1)/2) * (W/nf + 0.18u)'"
as="'int((nf+2)/2) * W/nf * 0.18u'"
ps="'2*int((nf+2)/2) * (W/nf + 0.18u)'"
nrd="'0.18u / W'" nrs="'0.18u / W'"
sa=0 sb=0 sd=0
model=nfet_03v3
spiceprefix=X
}
C {devices/iopin.sym} 4820 -1480 0 0 {name=p2 lab=vdd}
C {devices/iopin.sym} 4820 -920 0 0 {name=p3 lab=vss}
C {devices/iopin.sym} 4820 -1200 0 0 {name=p4 lab=vosc}
C {devices/iopin.sym} 1520 -1000 0 1 {name=p5 lab=vctrl
W=1.0u}
C {libs/core_analog/asc_delay/asc_delay.sym} 4700 -1200 0 0 {name=x1}
C {symbols/pfet_03v3.sym} 2980 -1260 0 0 {name=M31
L=0.5u
W=1.0u
nf=1
m=1
ad="'int((nf+1)/2) * W/nf * 0.18u'"
pd="'2*int((nf+1)/2) * (W/nf + 0.18u)'"
as="'int((nf+2)/2) * W/nf * 0.18u'"
ps="'2*int((nf+2)/2) * (W/nf + 0.18u)'"
nrd="'0.18u / W'" nrs="'0.18u / W'"
sa=0 sb=0 sd=0
model=pfet_03v3
spiceprefix=X
}
C {symbols/nfet_03v3.sym} 2980 -1140 0 0 {name=M32
L=0.5u
W=1.0u
nf=1
m=1
ad="'int((nf+1)/2) * W/nf * 0.18u'"
pd="'2*int((nf+1)/2) * (W/nf + 0.18u)'"
as="'int((nf+2)/2) * W/nf * 0.18u'"
ps="'2*int((nf+2)/2) * (W/nf + 0.18u)'"
nrd="'0.18u / W'" nrs="'0.18u / W'"
sa=0 sb=0 sd=0
model=nfet_03v3
spiceprefix=X
}
C {symbols/pfet_03v3.sym} 3140 -1260 0 0 {name=M33
L=0.5u
W=1.0u
nf=1
m=1
ad="'int((nf+1)/2) * W/nf * 0.18u'"
pd="'2*int((nf+1)/2) * (W/nf + 0.18u)'"
as="'int((nf+2)/2) * W/nf * 0.18u'"
ps="'2*int((nf+2)/2) * (W/nf + 0.18u)'"
nrd="'0.18u / W'" nrs="'0.18u / W'"
sa=0 sb=0 sd=0
model=pfet_03v3
spiceprefix=X
}
C {symbols/nfet_03v3.sym} 3140 -1140 0 0 {name=M34
L=0.5u
W=1.0u
nf=1
m=1
ad="'int((nf+1)/2) * W/nf * 0.18u'"
pd="'2*int((nf+1)/2) * (W/nf + 0.18u)'"
as="'int((nf+2)/2) * W/nf * 0.18u'"
ps="'2*int((nf+2)/2) * (W/nf + 0.18u)'"
nrd="'0.18u / W'" nrs="'0.18u / W'"
sa=0 sb=0 sd=0
model=nfet_03v3
spiceprefix=X
}
C {symbols/pfet_03v3.sym} 2980 -1400 0 0 {name=M35
L=0.5u
W=1.0u
nf=1
m=1
ad="'int((nf+1)/2) * W/nf * 0.18u'"
pd="'2*int((nf+1)/2) * (W/nf + 0.18u)'"
as="'int((nf+2)/2) * W/nf * 0.18u'"
ps="'2*int((nf+2)/2) * (W/nf + 0.18u)'"
nrd="'0.18u / W'" nrs="'0.18u / W'"
sa=0 sb=0 sd=0
model=pfet_03v3
spiceprefix=X
}
C {symbols/nfet_03v3.sym} 2980 -1000 0 0 {name=M36
L=0.5u
W=1.0u
nf=1
m=1
ad="'int((nf+1)/2) * W/nf * 0.18u'"
pd="'2*int((nf+1)/2) * (W/nf + 0.18u)'"
as="'int((nf+2)/2) * W/nf * 0.18u'"
ps="'2*int((nf+2)/2) * (W/nf + 0.18u)'"
nrd="'0.18u / W'" nrs="'0.18u / W'"
sa=0 sb=0 sd=0
model=nfet_03v3
spiceprefix=X
}
C {symbols/pfet_03v3.sym} 3140 -1400 0 0 {name=M37
L=0.5u
W=1.0u
nf=1
m=1
ad="'int((nf+1)/2) * W/nf * 0.18u'"
pd="'2*int((nf+1)/2) * (W/nf + 0.18u)'"
as="'int((nf+2)/2) * W/nf * 0.18u'"
ps="'2*int((nf+2)/2) * (W/nf + 0.18u)'"
nrd="'0.18u / W'" nrs="'0.18u / W'"
sa=0 sb=0 sd=0
model=pfet_03v3
spiceprefix=X
}
C {symbols/nfet_03v3.sym} 3140 -1000 0 0 {name=M38
L=0.5u
W=1.0u
nf=1
m=1
ad="'int((nf+1)/2) * W/nf * 0.18u'"
pd="'2*int((nf+1)/2) * (W/nf + 0.18u)'"
as="'int((nf+2)/2) * W/nf * 0.18u'"
ps="'2*int((nf+2)/2) * (W/nf + 0.18u)'"
nrd="'0.18u / W'" nrs="'0.18u / W'"
sa=0 sb=0 sd=0
model=nfet_03v3
spiceprefix=X
}
C {symbols/pfet_03v3.sym} 3300 -1260 0 0 {name=M39
L=0.5u
W=1.0u
nf=1
m=1
ad="'int((nf+1)/2) * W/nf * 0.18u'"
pd="'2*int((nf+1)/2) * (W/nf + 0.18u)'"
as="'int((nf+2)/2) * W/nf * 0.18u'"
ps="'2*int((nf+2)/2) * (W/nf + 0.18u)'"
nrd="'0.18u / W'" nrs="'0.18u / W'"
sa=0 sb=0 sd=0
model=pfet_03v3
spiceprefix=X
}
C {symbols/nfet_03v3.sym} 3300 -1140 0 0 {name=M40
L=0.5u
W=1.0u
nf=1
m=1
ad="'int((nf+1)/2) * W/nf * 0.18u'"
pd="'2*int((nf+1)/2) * (W/nf + 0.18u)'"
as="'int((nf+2)/2) * W/nf * 0.18u'"
ps="'2*int((nf+2)/2) * (W/nf + 0.18u)'"
nrd="'0.18u / W'" nrs="'0.18u / W'"
sa=0 sb=0 sd=0
model=nfet_03v3
spiceprefix=X
}
C {symbols/pfet_03v3.sym} 3460 -1260 0 0 {name=M41
L=0.5u
W=1.0u
nf=1
m=1
ad="'int((nf+1)/2) * W/nf * 0.18u'"
pd="'2*int((nf+1)/2) * (W/nf + 0.18u)'"
as="'int((nf+2)/2) * W/nf * 0.18u'"
ps="'2*int((nf+2)/2) * (W/nf + 0.18u)'"
nrd="'0.18u / W'" nrs="'0.18u / W'"
sa=0 sb=0 sd=0
model=pfet_03v3
spiceprefix=X
}
C {symbols/nfet_03v3.sym} 3460 -1140 0 0 {name=M42
L=0.5u
W=1.0u
nf=1
m=1
ad="'int((nf+1)/2) * W/nf * 0.18u'"
pd="'2*int((nf+1)/2) * (W/nf + 0.18u)'"
as="'int((nf+2)/2) * W/nf * 0.18u'"
ps="'2*int((nf+2)/2) * (W/nf + 0.18u)'"
nrd="'0.18u / W'" nrs="'0.18u / W'"
sa=0 sb=0 sd=0
model=nfet_03v3
spiceprefix=X
}
C {symbols/pfet_03v3.sym} 3300 -1400 0 0 {name=M43
L=0.5u
W=1.0u
nf=1
m=1
ad="'int((nf+1)/2) * W/nf * 0.18u'"
pd="'2*int((nf+1)/2) * (W/nf + 0.18u)'"
as="'int((nf+2)/2) * W/nf * 0.18u'"
ps="'2*int((nf+2)/2) * (W/nf + 0.18u)'"
nrd="'0.18u / W'" nrs="'0.18u / W'"
sa=0 sb=0 sd=0
model=pfet_03v3
spiceprefix=X
}
C {symbols/nfet_03v3.sym} 3300 -1000 0 0 {name=M44
L=0.5u
W=1.0u
nf=1
m=1
ad="'int((nf+1)/2) * W/nf * 0.18u'"
pd="'2*int((nf+1)/2) * (W/nf + 0.18u)'"
as="'int((nf+2)/2) * W/nf * 0.18u'"
ps="'2*int((nf+2)/2) * (W/nf + 0.18u)'"
nrd="'0.18u / W'" nrs="'0.18u / W'"
sa=0 sb=0 sd=0
model=nfet_03v3
spiceprefix=X
}
C {symbols/pfet_03v3.sym} 3460 -1400 0 0 {name=M45
L=0.5u
W=1.0u
nf=1
m=1
ad="'int((nf+1)/2) * W/nf * 0.18u'"
pd="'2*int((nf+1)/2) * (W/nf + 0.18u)'"
as="'int((nf+2)/2) * W/nf * 0.18u'"
ps="'2*int((nf+2)/2) * (W/nf + 0.18u)'"
nrd="'0.18u / W'" nrs="'0.18u / W'"
sa=0 sb=0 sd=0
model=pfet_03v3
spiceprefix=X
}
C {symbols/nfet_03v3.sym} 3460 -1000 0 0 {name=M46
L=0.5u
W=1.0u
nf=1
m=1
ad="'int((nf+1)/2) * W/nf * 0.18u'"
pd="'2*int((nf+1)/2) * (W/nf + 0.18u)'"
as="'int((nf+2)/2) * W/nf * 0.18u'"
ps="'2*int((nf+2)/2) * (W/nf + 0.18u)'"
nrd="'0.18u / W'" nrs="'0.18u / W'"
sa=0 sb=0 sd=0
model=nfet_03v3
spiceprefix=X
}
C {symbols/pfet_03v3.sym} 3660 -1260 0 0 {name=M47
L=0.5u
W=1.0u
nf=1
m=1
ad="'int((nf+1)/2) * W/nf * 0.18u'"
pd="'2*int((nf+1)/2) * (W/nf + 0.18u)'"
as="'int((nf+2)/2) * W/nf * 0.18u'"
ps="'2*int((nf+2)/2) * (W/nf + 0.18u)'"
nrd="'0.18u / W'" nrs="'0.18u / W'"
sa=0 sb=0 sd=0
model=pfet_03v3
spiceprefix=X
}
C {symbols/nfet_03v3.sym} 3660 -1140 0 0 {name=M48
L=0.5u
W=1.0u
nf=1
m=1
ad="'int((nf+1)/2) * W/nf * 0.18u'"
pd="'2*int((nf+1)/2) * (W/nf + 0.18u)'"
as="'int((nf+2)/2) * W/nf * 0.18u'"
ps="'2*int((nf+2)/2) * (W/nf + 0.18u)'"
nrd="'0.18u / W'" nrs="'0.18u / W'"
sa=0 sb=0 sd=0
model=nfet_03v3
spiceprefix=X
}
C {symbols/pfet_03v3.sym} 3820 -1260 0 0 {name=M49
L=0.5u
W=1.0u
nf=1
m=1
ad="'int((nf+1)/2) * W/nf * 0.18u'"
pd="'2*int((nf+1)/2) * (W/nf + 0.18u)'"
as="'int((nf+2)/2) * W/nf * 0.18u'"
ps="'2*int((nf+2)/2) * (W/nf + 0.18u)'"
nrd="'0.18u / W'" nrs="'0.18u / W'"
sa=0 sb=0 sd=0
model=pfet_03v3
spiceprefix=X
}
C {symbols/nfet_03v3.sym} 3820 -1140 0 0 {name=M50
L=0.5u
W=1.0u
nf=1
m=1
ad="'int((nf+1)/2) * W/nf * 0.18u'"
pd="'2*int((nf+1)/2) * (W/nf + 0.18u)'"
as="'int((nf+2)/2) * W/nf * 0.18u'"
ps="'2*int((nf+2)/2) * (W/nf + 0.18u)'"
nrd="'0.18u / W'" nrs="'0.18u / W'"
sa=0 sb=0 sd=0
model=nfet_03v3
spiceprefix=X
}
C {symbols/pfet_03v3.sym} 3660 -1400 0 0 {name=M51
L=0.5u
W=1.0u
nf=1
m=1
ad="'int((nf+1)/2) * W/nf * 0.18u'"
pd="'2*int((nf+1)/2) * (W/nf + 0.18u)'"
as="'int((nf+2)/2) * W/nf * 0.18u'"
ps="'2*int((nf+2)/2) * (W/nf + 0.18u)'"
nrd="'0.18u / W'" nrs="'0.18u / W'"
sa=0 sb=0 sd=0
model=pfet_03v3
spiceprefix=X
}
C {symbols/nfet_03v3.sym} 3660 -1000 0 0 {name=M52
L=0.5u
W=1.0u
nf=1
m=1
ad="'int((nf+1)/2) * W/nf * 0.18u'"
pd="'2*int((nf+1)/2) * (W/nf + 0.18u)'"
as="'int((nf+2)/2) * W/nf * 0.18u'"
ps="'2*int((nf+2)/2) * (W/nf + 0.18u)'"
nrd="'0.18u / W'" nrs="'0.18u / W'"
sa=0 sb=0 sd=0
model=nfet_03v3
spiceprefix=X
}
C {symbols/pfet_03v3.sym} 3820 -1400 0 0 {name=M53
L=0.5u
W=1.0u
nf=1
m=1
ad="'int((nf+1)/2) * W/nf * 0.18u'"
pd="'2*int((nf+1)/2) * (W/nf + 0.18u)'"
as="'int((nf+2)/2) * W/nf * 0.18u'"
ps="'2*int((nf+2)/2) * (W/nf + 0.18u)'"
nrd="'0.18u / W'" nrs="'0.18u / W'"
sa=0 sb=0 sd=0
model=pfet_03v3
spiceprefix=X
}
C {symbols/nfet_03v3.sym} 3820 -1000 0 0 {name=M54
L=0.5u
W=1.0u
nf=1
m=1
ad="'int((nf+1)/2) * W/nf * 0.18u'"
pd="'2*int((nf+1)/2) * (W/nf + 0.18u)'"
as="'int((nf+2)/2) * W/nf * 0.18u'"
ps="'2*int((nf+2)/2) * (W/nf + 0.18u)'"
nrd="'0.18u / W'" nrs="'0.18u / W'"
sa=0 sb=0 sd=0
model=nfet_03v3
spiceprefix=X
}
C {symbols/pfet_03v3.sym} 3980 -1260 0 0 {name=M55
L=0.5u
W=1.0u
nf=1
m=1
ad="'int((nf+1)/2) * W/nf * 0.18u'"
pd="'2*int((nf+1)/2) * (W/nf + 0.18u)'"
as="'int((nf+2)/2) * W/nf * 0.18u'"
ps="'2*int((nf+2)/2) * (W/nf + 0.18u)'"
nrd="'0.18u / W'" nrs="'0.18u / W'"
sa=0 sb=0 sd=0
model=pfet_03v3
spiceprefix=X
}
C {symbols/nfet_03v3.sym} 3980 -1140 0 0 {name=M56
L=0.5u
W=1.0u
nf=1
m=1
ad="'int((nf+1)/2) * W/nf * 0.18u'"
pd="'2*int((nf+1)/2) * (W/nf + 0.18u)'"
as="'int((nf+2)/2) * W/nf * 0.18u'"
ps="'2*int((nf+2)/2) * (W/nf + 0.18u)'"
nrd="'0.18u / W'" nrs="'0.18u / W'"
sa=0 sb=0 sd=0
model=nfet_03v3
spiceprefix=X
}
C {symbols/pfet_03v3.sym} 4140 -1260 0 0 {name=M57
L=0.5u
W=1.0u
nf=1
m=1
ad="'int((nf+1)/2) * W/nf * 0.18u'"
pd="'2*int((nf+1)/2) * (W/nf + 0.18u)'"
as="'int((nf+2)/2) * W/nf * 0.18u'"
ps="'2*int((nf+2)/2) * (W/nf + 0.18u)'"
nrd="'0.18u / W'" nrs="'0.18u / W'"
sa=0 sb=0 sd=0
model=pfet_03v3
spiceprefix=X
}
C {symbols/nfet_03v3.sym} 4140 -1140 0 0 {name=M58
L=0.5u
W=1.0u
nf=1
m=1
ad="'int((nf+1)/2) * W/nf * 0.18u'"
pd="'2*int((nf+1)/2) * (W/nf + 0.18u)'"
as="'int((nf+2)/2) * W/nf * 0.18u'"
ps="'2*int((nf+2)/2) * (W/nf + 0.18u)'"
nrd="'0.18u / W'" nrs="'0.18u / W'"
sa=0 sb=0 sd=0
model=nfet_03v3
spiceprefix=X
}
C {symbols/pfet_03v3.sym} 3980 -1400 0 0 {name=M59
L=0.5u
W=1.0u
nf=1
m=1
ad="'int((nf+1)/2) * W/nf * 0.18u'"
pd="'2*int((nf+1)/2) * (W/nf + 0.18u)'"
as="'int((nf+2)/2) * W/nf * 0.18u'"
ps="'2*int((nf+2)/2) * (W/nf + 0.18u)'"
nrd="'0.18u / W'" nrs="'0.18u / W'"
sa=0 sb=0 sd=0
model=pfet_03v3
spiceprefix=X
}
C {symbols/nfet_03v3.sym} 3980 -1000 0 0 {name=M60
L=0.5u
W=1.0u
nf=1
m=1
ad="'int((nf+1)/2) * W/nf * 0.18u'"
pd="'2*int((nf+1)/2) * (W/nf + 0.18u)'"
as="'int((nf+2)/2) * W/nf * 0.18u'"
ps="'2*int((nf+2)/2) * (W/nf + 0.18u)'"
nrd="'0.18u / W'" nrs="'0.18u / W'"
sa=0 sb=0 sd=0
model=nfet_03v3
spiceprefix=X
}
C {symbols/pfet_03v3.sym} 4140 -1400 0 0 {name=M61
L=0.5u
W=1.0u
nf=1
m=1
ad="'int((nf+1)/2) * W/nf * 0.18u'"
pd="'2*int((nf+1)/2) * (W/nf + 0.18u)'"
as="'int((nf+2)/2) * W/nf * 0.18u'"
ps="'2*int((nf+2)/2) * (W/nf + 0.18u)'"
nrd="'0.18u / W'" nrs="'0.18u / W'"
sa=0 sb=0 sd=0
model=pfet_03v3
spiceprefix=X
}
C {symbols/nfet_03v3.sym} 4140 -1000 0 0 {name=M62
L=0.5u
W=1.0u
nf=1
m=1
ad="'int((nf+1)/2) * W/nf * 0.18u'"
pd="'2*int((nf+1)/2) * (W/nf + 0.18u)'"
as="'int((nf+2)/2) * W/nf * 0.18u'"
ps="'2*int((nf+2)/2) * (W/nf + 0.18u)'"
nrd="'0.18u / W'" nrs="'0.18u / W'"
sa=0 sb=0 sd=0
model=nfet_03v3
spiceprefix=X
}
C {symbols/pfet_03v3.sym} 4340 -1260 0 0 {name=M63
L=0.5u
W=1.0u
nf=1
m=1
ad="'int((nf+1)/2) * W/nf * 0.18u'"
pd="'2*int((nf+1)/2) * (W/nf + 0.18u)'"
as="'int((nf+2)/2) * W/nf * 0.18u'"
ps="'2*int((nf+2)/2) * (W/nf + 0.18u)'"
nrd="'0.18u / W'" nrs="'0.18u / W'"
sa=0 sb=0 sd=0
model=pfet_03v3
spiceprefix=X
}
C {symbols/nfet_03v3.sym} 4340 -1140 0 0 {name=M64
L=0.5u
W=1.0u
nf=1
m=1
ad="'int((nf+1)/2) * W/nf * 0.18u'"
pd="'2*int((nf+1)/2) * (W/nf + 0.18u)'"
as="'int((nf+2)/2) * W/nf * 0.18u'"
ps="'2*int((nf+2)/2) * (W/nf + 0.18u)'"
nrd="'0.18u / W'" nrs="'0.18u / W'"
sa=0 sb=0 sd=0
model=nfet_03v3
spiceprefix=X
}
C {symbols/pfet_03v3.sym} 4500 -1260 0 0 {name=M65
L=0.5u
W=1.0u
nf=1
m=1
ad="'int((nf+1)/2) * W/nf * 0.18u'"
pd="'2*int((nf+1)/2) * (W/nf + 0.18u)'"
as="'int((nf+2)/2) * W/nf * 0.18u'"
ps="'2*int((nf+2)/2) * (W/nf + 0.18u)'"
nrd="'0.18u / W'" nrs="'0.18u / W'"
sa=0 sb=0 sd=0
model=pfet_03v3
spiceprefix=X
}
C {symbols/nfet_03v3.sym} 4500 -1140 0 0 {name=M66
L=0.5u
W=1.0u
nf=1
m=1
ad="'int((nf+1)/2) * W/nf * 0.18u'"
pd="'2*int((nf+1)/2) * (W/nf + 0.18u)'"
as="'int((nf+2)/2) * W/nf * 0.18u'"
ps="'2*int((nf+2)/2) * (W/nf + 0.18u)'"
nrd="'0.18u / W'" nrs="'0.18u / W'"
sa=0 sb=0 sd=0
model=nfet_03v3
spiceprefix=X
}
C {symbols/pfet_03v3.sym} 4340 -1400 0 0 {name=M67
L=0.5u
W=1.0u
nf=1
m=1
ad="'int((nf+1)/2) * W/nf * 0.18u'"
pd="'2*int((nf+1)/2) * (W/nf + 0.18u)'"
as="'int((nf+2)/2) * W/nf * 0.18u'"
ps="'2*int((nf+2)/2) * (W/nf + 0.18u)'"
nrd="'0.18u / W'" nrs="'0.18u / W'"
sa=0 sb=0 sd=0
model=pfet_03v3
spiceprefix=X
}
C {symbols/nfet_03v3.sym} 4340 -1000 0 0 {name=M68
L=0.5u
W=1.0u
nf=1
m=1
ad="'int((nf+1)/2) * W/nf * 0.18u'"
pd="'2*int((nf+1)/2) * (W/nf + 0.18u)'"
as="'int((nf+2)/2) * W/nf * 0.18u'"
ps="'2*int((nf+2)/2) * (W/nf + 0.18u)'"
nrd="'0.18u / W'" nrs="'0.18u / W'"
sa=0 sb=0 sd=0
model=nfet_03v3
spiceprefix=X
}
C {symbols/pfet_03v3.sym} 4500 -1400 0 0 {name=M69
L=0.5u
W=1.0u
nf=1
m=1
ad="'int((nf+1)/2) * W/nf * 0.18u'"
pd="'2*int((nf+1)/2) * (W/nf + 0.18u)'"
as="'int((nf+2)/2) * W/nf * 0.18u'"
ps="'2*int((nf+2)/2) * (W/nf + 0.18u)'"
nrd="'0.18u / W'" nrs="'0.18u / W'"
sa=0 sb=0 sd=0
model=pfet_03v3
spiceprefix=X
}
C {symbols/nfet_03v3.sym} 4500 -1000 0 0 {name=M70
L=0.5u
W=1.0u
nf=1
m=1
ad="'int((nf+1)/2) * W/nf * 0.18u'"
pd="'2*int((nf+1)/2) * (W/nf + 0.18u)'"
as="'int((nf+2)/2) * W/nf * 0.18u'"
ps="'2*int((nf+2)/2) * (W/nf + 0.18u)'"
nrd="'0.18u / W'" nrs="'0.18u / W'"
sa=0 sb=0 sd=0
model=nfet_03v3
spiceprefix=X
}
